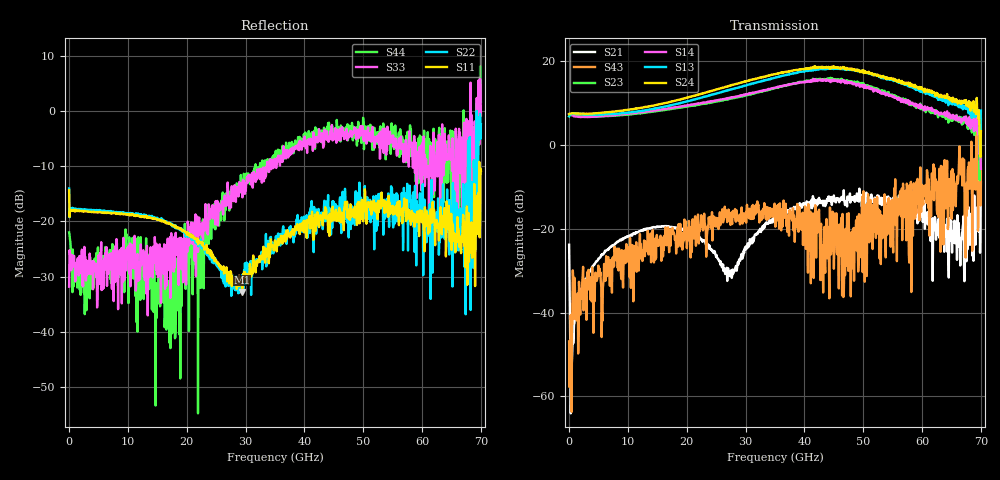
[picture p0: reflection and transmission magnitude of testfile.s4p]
!Pstart = -2.000000E+001
!Pstop = -1.000000E+001
!Pstep = 2.564103E-001
! 4/23/2026 4:38:33 PM
! C:\ANRITSUVNA\TEMP\TEMP.S4P
! CHANNEL.1
! TR.MEASUREMENT
! CORRECTED.DATA
! RF.CORRECTION: FULL.FOUR.PORT.CAL.PORT.1.2.3.4
! AVERAGING.OFF
! IF.BANDWIDTH: NO.IFBW
! SWEEPTYPE:  FREQ.SWEEP(Linear)
! Reference Plane Port Info
! DISTANCE:  0  m  0  m  0  m  0  m
! TIME:  0  s  0  s  0  s  0  s
! PHASE.OFFSET:  0 °  0 °  0 °  0 °
! LOSS:  0  dB  0  dB  0  dB  0  dB
! REF.LOSS:  0  dB  0  dB  0  dB  0  dB
! REF.FREQ:  0  Hz  0  Hz  0  Hz  0  Hz
! Power Info
! POWER:  -20  dBm  -20  dBm  -20  dBm  -20  dBm
! EFF.POWER:  -20  dBm  -20  dBm  -40  dBm  -40  dBm
! SOURCE.ATTEN:  0  dB  0  dB  20  dB  20  dB
! TEST.ATTEN:  0  dB  0  dB  20  dB  20  dB
! Created with skrf 1.9.0 (http://scikit-rf.org).
# Hz S RI R 50.0
!freq ReS11 ImS11 ReS12 ImS12 ReS13 ImS13
! ReS14 ImS14
! ReS21 ImS21 ReS22 ImS22 ReS23 ImS23
! ReS24 ImS24
! ReS31 ImS31 ReS32 ImS32 ReS33 ImS33
! ReS34 ImS34
! ReS41 ImS41 ReS42 ImS42 ReS43 ImS43
! ReS44 ImS44
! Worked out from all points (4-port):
!   1001 points, 10 MHz to 70 GHz, reference 50 ohm
!   strongest paths, dB at 10 MHz, 17.51 GHz, 35.01 GHz, 52.5 GHz, 70 GHz:
!     S24: 7.4, 10.4, 16.9, 16.5, 3.3
!     S13: 6.9, 9.6, 16.1, 16.6, 8.2
!     S14: 7.4, 8.9, 13.7, 12.8, -5.7
!     S23: 6.9, 8.7, 13.6, 13.3, 6.3
!     S43: -46.9, -21.2, -16.5, -18.1, -2.7
!     S21: -23.8, -19.6, -17.7, -13.5, -8.8
!   lowest |S11| = -32.8 dB at 29.41 GHz (marker M1), VSWR 1.05, Z = 49.3 - j2.17 ohm
!   |S11| at or under -10 dB: start of sweep to 69.71 GHz; 69.72432 GHz to end of sweep
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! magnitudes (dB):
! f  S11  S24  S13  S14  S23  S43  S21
! 10 MHz  -14.3  7.4  6.9  7.4  6.9  -46.9  -23.8
! 569.9 MHz  -17.9  7.6  7.4  7.1  7.2  -38.4  -48.2
! 16.88 GHz  -20.2  10.2  9.4  8.8  8.5  -22.3  -19.5
! 29.41 GHz  -32.8  14.9  14.0  11.9  11.6  -18.0  -27.2
! 46.76 GHz  -17.7  18.2  18.2  15.0  15.5  -30.6  -13.3
! 66.85 GHz  -21.9  10.2  9.4  6.0  6.1  -9.7  -20.7
! 70 GHz  -10.8  3.3  8.2  -5.7  6.3  -2.7  -8.8
